One B-rep face of a CAD part: STEP entity #52650.
In plain terms, the planar face has unit normal (0, 0, 1).
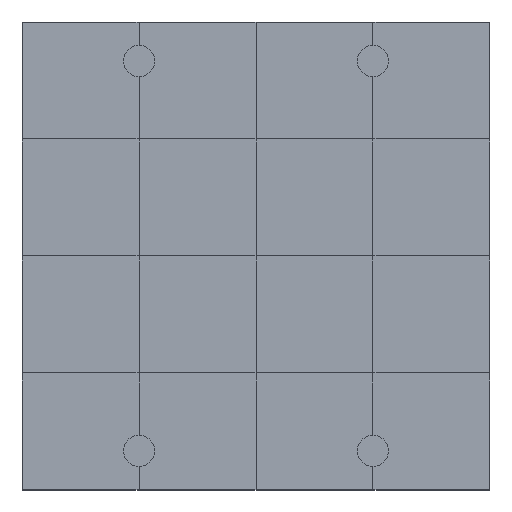
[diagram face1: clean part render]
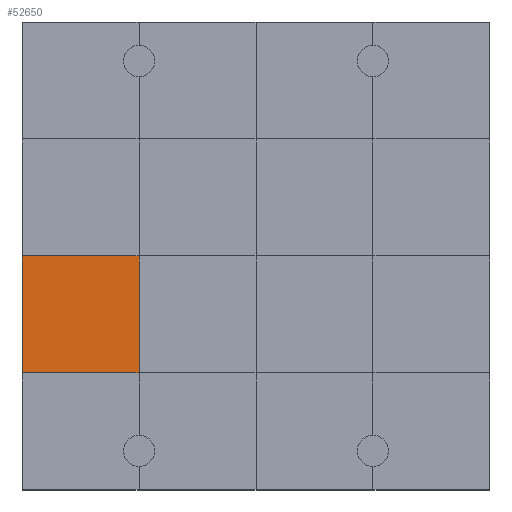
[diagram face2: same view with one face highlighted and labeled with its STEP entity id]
Its self-contained STEP definition (entity closure, numbers rounded to 3 decimals):
#52200 = VERTEX_POINT('',#52201);
#52201 = CARTESIAN_POINT('',(0.,3.,1.2));
#52215 = PLANE('',#52216);
#52216 = AXIS2_PLACEMENT_3D('',#52217,#52218,#52219);
#52217 = CARTESIAN_POINT('',(0.,3.,0.));
#52218 = DIRECTION('',(1.,0.,-0.));
#52219 = DIRECTION('',(0.,0.,1.));
#52241 = PLANE('',#52242);
#52242 = AXIS2_PLACEMENT_3D('',#52243,#52244,#52245);
#52243 = CARTESIAN_POINT('',(0.,0.,1.2));
#52244 = DIRECTION('',(0.,0.,1.));
#52245 = DIRECTION('',(1.,0.,-0.));
#52392 = VERTEX_POINT('',#52393);
#52393 = CARTESIAN_POINT('',(3.,3.,1.2));
#52414 = EDGE_CURVE('',#52200,#52392,#52415,.T.);
#52415 = SURFACE_CURVE('',#52416,(#52420,#52427),.PCURVE_S1.);
#52416 = LINE('',#52417,#52418);
#52417 = CARTESIAN_POINT('',(0.,3.,1.2));
#52418 = VECTOR('',#52419,1.);
#52419 = DIRECTION('',(1.,0.,-0.));
#52420 = PCURVE('',#52241,#52421);
#52421 = DEFINITIONAL_REPRESENTATION('',(#52422),#52426);
#52422 = LINE('',#52423,#52424);
#52423 = CARTESIAN_POINT('',(0.,3.));
#52424 = VECTOR('',#52425,1.);
#52425 = DIRECTION('',(1.,0.));
#52426 = ( GEOMETRIC_REPRESENTATION_CONTEXT(2) 
PARAMETRIC_REPRESENTATION_CONTEXT() REPRESENTATION_CONTEXT('2D SPACE',''
  ) );
#52427 = PCURVE('',#52428,#52433);
#52428 = PLANE('',#52429);
#52429 = AXIS2_PLACEMENT_3D('',#52430,#52431,#52432);
#52430 = CARTESIAN_POINT('',(0.,3.,1.2));
#52431 = DIRECTION('',(0.,0.,1.));
#52432 = DIRECTION('',(1.,0.,-0.));
#52433 = DEFINITIONAL_REPRESENTATION('',(#52434),#52438);
#52434 = LINE('',#52435,#52436);
#52435 = CARTESIAN_POINT('',(0.,0.));
#52436 = VECTOR('',#52437,1.);
#52437 = DIRECTION('',(1.,0.));
#52438 = ( GEOMETRIC_REPRESENTATION_CONTEXT(2) 
PARAMETRIC_REPRESENTATION_CONTEXT() REPRESENTATION_CONTEXT('2D SPACE',''
  ) );
#52473 = VERTEX_POINT('',#52474);
#52474 = CARTESIAN_POINT('',(0.,6.,1.2));
#52500 = EDGE_CURVE('',#52200,#52473,#52501,.T.);
#52501 = SURFACE_CURVE('',#52502,(#52506,#52513),.PCURVE_S1.);
#52502 = LINE('',#52503,#52504);
#52503 = CARTESIAN_POINT('',(0.,3.,1.2));
#52504 = VECTOR('',#52505,1.);
#52505 = DIRECTION('',(-0.,1.,0.));
#52506 = PCURVE('',#52215,#52507);
#52507 = DEFINITIONAL_REPRESENTATION('',(#52508),#52512);
#52508 = LINE('',#52509,#52510);
#52509 = CARTESIAN_POINT('',(1.2,0.));
#52510 = VECTOR('',#52511,1.);
#52511 = DIRECTION('',(0.,-1.));
#52512 = ( GEOMETRIC_REPRESENTATION_CONTEXT(2) 
PARAMETRIC_REPRESENTATION_CONTEXT() REPRESENTATION_CONTEXT('2D SPACE',''
  ) );
#52513 = PCURVE('',#52428,#52514);
#52514 = DEFINITIONAL_REPRESENTATION('',(#52515),#52519);
#52515 = LINE('',#52516,#52517);
#52516 = CARTESIAN_POINT('',(0.,0.));
#52517 = VECTOR('',#52518,1.);
#52518 = DIRECTION('',(0.,1.));
#52519 = ( GEOMETRIC_REPRESENTATION_CONTEXT(2) 
PARAMETRIC_REPRESENTATION_CONTEXT() REPRESENTATION_CONTEXT('2D SPACE',''
  ) );
#52650 = ADVANCED_FACE('',(#52651),#52428,.T.);
#52651 = FACE_BOUND('',#52652,.T.);
#52652 = EDGE_LOOP('',(#52653,#52654,#52655,#52683));
#52653 = ORIENTED_EDGE('',*,*,#52500,.F.);
#52654 = ORIENTED_EDGE('',*,*,#52414,.T.);
#52655 = ORIENTED_EDGE('',*,*,#52656,.T.);
#52656 = EDGE_CURVE('',#52392,#52657,#52659,.T.);
#52657 = VERTEX_POINT('',#52658);
#52658 = CARTESIAN_POINT('',(3.,6.,1.2));
#52659 = SURFACE_CURVE('',#52660,(#52664,#52671),.PCURVE_S1.);
#52660 = LINE('',#52661,#52662);
#52661 = CARTESIAN_POINT('',(3.,3.,1.2));
#52662 = VECTOR('',#52663,1.);
#52663 = DIRECTION('',(-0.,1.,0.));
#52664 = PCURVE('',#52428,#52665);
#52665 = DEFINITIONAL_REPRESENTATION('',(#52666),#52670);
#52666 = LINE('',#52667,#52668);
#52667 = CARTESIAN_POINT('',(3.,0.));
#52668 = VECTOR('',#52669,1.);
#52669 = DIRECTION('',(0.,1.));
#52670 = ( GEOMETRIC_REPRESENTATION_CONTEXT(2) 
PARAMETRIC_REPRESENTATION_CONTEXT() REPRESENTATION_CONTEXT('2D SPACE',''
  ) );
#52671 = PCURVE('',#52672,#52677);
#52672 = PLANE('',#52673);
#52673 = AXIS2_PLACEMENT_3D('',#52674,#52675,#52676);
#52674 = CARTESIAN_POINT('',(3.,3.,1.2));
#52675 = DIRECTION('',(0.,0.,1.));
#52676 = DIRECTION('',(1.,0.,-0.));
#52677 = DEFINITIONAL_REPRESENTATION('',(#52678),#52682);
#52678 = LINE('',#52679,#52680);
#52679 = CARTESIAN_POINT('',(0.,0.));
#52680 = VECTOR('',#52681,1.);
#52681 = DIRECTION('',(0.,1.));
#52682 = ( GEOMETRIC_REPRESENTATION_CONTEXT(2) 
PARAMETRIC_REPRESENTATION_CONTEXT() REPRESENTATION_CONTEXT('2D SPACE',''
  ) );
#52683 = ORIENTED_EDGE('',*,*,#52684,.F.);
#52684 = EDGE_CURVE('',#52473,#52657,#52685,.T.);
#52685 = SURFACE_CURVE('',#52686,(#52690,#52697),.PCURVE_S1.);
#52686 = LINE('',#52687,#52688);
#52687 = CARTESIAN_POINT('',(0.,6.,1.2));
#52688 = VECTOR('',#52689,1.);
#52689 = DIRECTION('',(1.,0.,-0.));
#52690 = PCURVE('',#52428,#52691);
#52691 = DEFINITIONAL_REPRESENTATION('',(#52692),#52696);
#52692 = LINE('',#52693,#52694);
#52693 = CARTESIAN_POINT('',(0.,3.));
#52694 = VECTOR('',#52695,1.);
#52695 = DIRECTION('',(1.,0.));
#52696 = ( GEOMETRIC_REPRESENTATION_CONTEXT(2) 
PARAMETRIC_REPRESENTATION_CONTEXT() REPRESENTATION_CONTEXT('2D SPACE',''
  ) );
#52697 = PCURVE('',#52698,#52703);
#52698 = PLANE('',#52699);
#52699 = AXIS2_PLACEMENT_3D('',#52700,#52701,#52702);
#52700 = CARTESIAN_POINT('',(0.,6.,1.2));
#52701 = DIRECTION('',(0.,0.,1.));
#52702 = DIRECTION('',(1.,0.,-0.));
#52703 = DEFINITIONAL_REPRESENTATION('',(#52704),#52708);
#52704 = LINE('',#52705,#52706);
#52705 = CARTESIAN_POINT('',(0.,0.));
#52706 = VECTOR('',#52707,1.);
#52707 = DIRECTION('',(1.,0.));
#52708 = ( GEOMETRIC_REPRESENTATION_CONTEXT(2) 
PARAMETRIC_REPRESENTATION_CONTEXT() REPRESENTATION_CONTEXT('2D SPACE',''
  ) );
